VERSION 5.7 ;
  NOWIREEXTENSIONATPIN ON ;
  DIVIDERCHAR "/" ;
  BUSBITCHARS "[]" ;
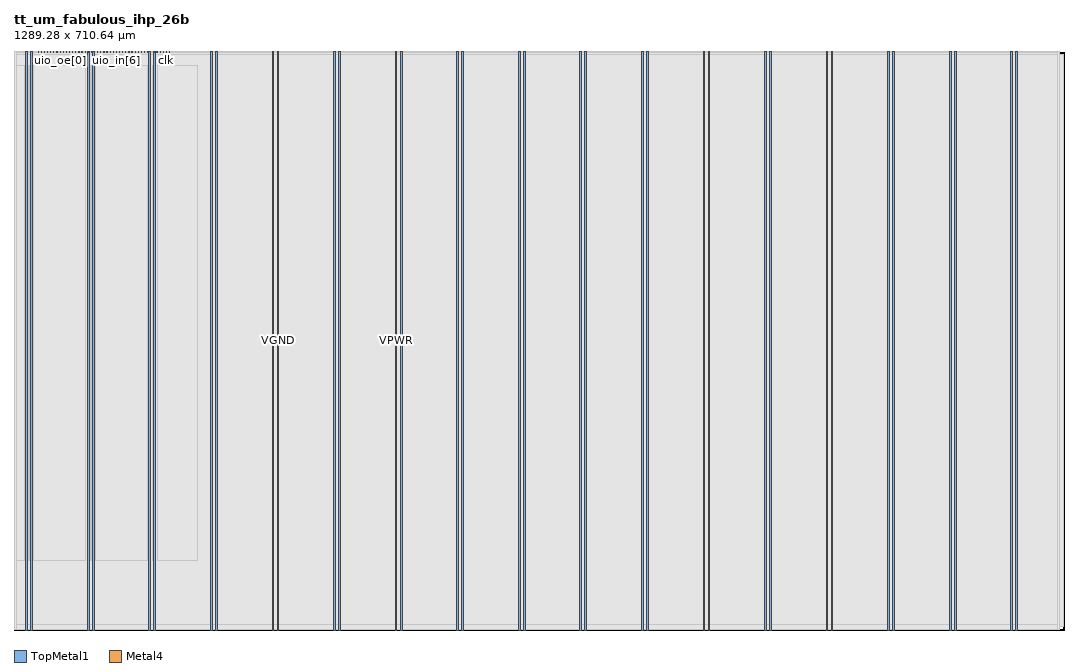
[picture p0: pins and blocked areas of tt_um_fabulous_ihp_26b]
MACRO tt_um_fabulous_ihp_26b
  CLASS BLOCK ;
  FOREIGN tt_um_fabulous_ihp_26b ;
  ORIGIN 0.000 0.000 ;
  SIZE 1289.280 BY 710.640 ;
  PIN VGND
    DIRECTION INOUT ;
    USE GROUND ;
    PORT
      LAYER TopMetal1 ;
        RECT 20.620 0.000 22.820 710.640 ;
    END
    PORT
      LAYER TopMetal1 ;
        RECT 96.220 0.000 98.420 710.640 ;
    END
    PORT
      LAYER TopMetal1 ;
        RECT 171.820 0.000 174.020 710.640 ;
    END
    PORT
      LAYER TopMetal1 ;
        RECT 247.420 0.000 249.620 710.640 ;
    END
    PORT
      LAYER TopMetal1 ;
        RECT 323.020 0.000 325.220 710.640 ;
    END
    PORT
      LAYER TopMetal1 ;
        RECT 398.620 0.000 400.820 710.640 ;
    END
    PORT
      LAYER TopMetal1 ;
        RECT 474.220 0.000 476.420 710.640 ;
    END
    PORT
      LAYER TopMetal1 ;
        RECT 549.820 0.000 552.020 710.640 ;
    END
    PORT
      LAYER TopMetal1 ;
        RECT 625.420 0.000 627.620 710.640 ;
    END
    PORT
      LAYER TopMetal1 ;
        RECT 701.020 0.000 703.220 710.640 ;
    END
    PORT
      LAYER TopMetal1 ;
        RECT 776.620 0.000 778.820 710.640 ;
    END
    PORT
      LAYER TopMetal1 ;
        RECT 852.220 0.000 854.420 710.640 ;
    END
    PORT
      LAYER TopMetal1 ;
        RECT 927.820 0.000 930.020 710.640 ;
    END
    PORT
      LAYER TopMetal1 ;
        RECT 1003.420 0.000 1005.620 710.640 ;
    END
    PORT
      LAYER TopMetal1 ;
        RECT 1079.020 0.000 1081.220 710.640 ;
    END
    PORT
      LAYER TopMetal1 ;
        RECT 1154.620 0.000 1156.820 710.640 ;
    END
    PORT
      LAYER TopMetal1 ;
        RECT 1230.220 0.000 1232.420 710.640 ;
    END
  END VGND
  PIN VPWR
    DIRECTION INOUT ;
    USE POWER ;
    PORT
      LAYER TopMetal1 ;
        RECT 14.420 0.000 16.620 710.640 ;
    END
    PORT
      LAYER TopMetal1 ;
        RECT 90.020 0.000 92.220 710.640 ;
    END
    PORT
      LAYER TopMetal1 ;
        RECT 165.620 0.000 167.820 710.640 ;
    END
    PORT
      LAYER TopMetal1 ;
        RECT 241.220 0.000 243.420 710.640 ;
    END
    PORT
      LAYER TopMetal1 ;
        RECT 316.820 0.000 319.020 710.640 ;
    END
    PORT
      LAYER TopMetal1 ;
        RECT 392.420 0.000 394.620 710.640 ;
    END
    PORT
      LAYER TopMetal1 ;
        RECT 468.020 0.000 470.220 710.640 ;
    END
    PORT
      LAYER TopMetal1 ;
        RECT 543.620 0.000 545.820 710.640 ;
    END
    PORT
      LAYER TopMetal1 ;
        RECT 619.220 0.000 621.420 710.640 ;
    END
    PORT
      LAYER TopMetal1 ;
        RECT 694.820 0.000 697.020 710.640 ;
    END
    PORT
      LAYER TopMetal1 ;
        RECT 770.420 0.000 772.620 710.640 ;
    END
    PORT
      LAYER TopMetal1 ;
        RECT 846.020 0.000 848.220 710.640 ;
    END
    PORT
      LAYER TopMetal1 ;
        RECT 921.620 0.000 923.820 710.640 ;
    END
    PORT
      LAYER TopMetal1 ;
        RECT 997.220 0.000 999.420 710.640 ;
    END
    PORT
      LAYER TopMetal1 ;
        RECT 1072.820 0.000 1075.020 710.640 ;
    END
    PORT
      LAYER TopMetal1 ;
        RECT 1148.420 0.000 1150.620 710.640 ;
    END
    PORT
      LAYER TopMetal1 ;
        RECT 1224.020 0.000 1226.220 710.640 ;
    END
  END VPWR
  PIN clk
    DIRECTION INPUT ;
    USE SIGNAL ;
    ANTENNAGATEAREA 2.901600 ;
    PORT
      LAYER Metal4 ;
        RECT 187.050 709.640 187.350 710.640 ;
    END
  END clk
  PIN ena
    DIRECTION INPUT ;
    USE SIGNAL ;
    PORT
      LAYER Metal4 ;
        RECT 190.890 709.640 191.190 710.640 ;
    END
  END ena
  PIN rst_n
    DIRECTION INPUT ;
    USE SIGNAL ;
    ANTENNAGATEAREA 0.180700 ;
    PORT
      LAYER Metal4 ;
        RECT 183.210 709.640 183.510 710.640 ;
    END
  END rst_n
  PIN ui_in[0]
    DIRECTION INPUT ;
    USE SIGNAL ;
    ANTENNAGATEAREA 0.180700 ;
    PORT
      LAYER Metal4 ;
        RECT 179.370 709.640 179.670 710.640 ;
    END
  END ui_in[0]
  PIN ui_in[1]
    DIRECTION INPUT ;
    USE SIGNAL ;
    ANTENNAGATEAREA 0.180700 ;
    PORT
      LAYER Metal4 ;
        RECT 175.530 709.640 175.830 710.640 ;
    END
  END ui_in[1]
  PIN ui_in[2]
    DIRECTION INPUT ;
    USE SIGNAL ;
    ANTENNAGATEAREA 0.335400 ;
    PORT
      LAYER Metal4 ;
        RECT 171.690 709.640 171.990 710.640 ;
    END
  END ui_in[2]
  PIN ui_in[3]
    DIRECTION INPUT ;
    USE SIGNAL ;
    ANTENNAGATEAREA 0.335400 ;
    PORT
      LAYER Metal4 ;
        RECT 167.850 709.640 168.150 710.640 ;
    END
  END ui_in[3]
  PIN ui_in[4]
    DIRECTION INPUT ;
    USE SIGNAL ;
    ANTENNAGATEAREA 0.335400 ;
    PORT
      LAYER Metal4 ;
        RECT 164.010 709.640 164.310 710.640 ;
    END
  END ui_in[4]
  PIN ui_in[5]
    DIRECTION INPUT ;
    USE SIGNAL ;
    ANTENNAGATEAREA 0.335400 ;
    PORT
      LAYER Metal4 ;
        RECT 160.170 709.640 160.470 710.640 ;
    END
  END ui_in[5]
  PIN ui_in[6]
    DIRECTION INPUT ;
    USE SIGNAL ;
    ANTENNAGATEAREA 0.335400 ;
    PORT
      LAYER Metal4 ;
        RECT 156.330 709.640 156.630 710.640 ;
    END
  END ui_in[6]
  PIN ui_in[7]
    DIRECTION INPUT ;
    USE SIGNAL ;
    ANTENNAGATEAREA 0.335400 ;
    ANTENNADIFFAREA 2.015400 ;
    PORT
      LAYER Metal4 ;
        RECT 152.490 709.640 152.790 710.640 ;
    END
  END ui_in[7]
  PIN uio_in[0]
    DIRECTION INPUT ;
    USE SIGNAL ;
    ANTENNAGATEAREA 0.335400 ;
    PORT
      LAYER Metal4 ;
        RECT 148.650 709.640 148.950 710.640 ;
    END
  END uio_in[0]
  PIN uio_in[1]
    DIRECTION INPUT ;
    USE SIGNAL ;
    ANTENNAGATEAREA 0.335400 ;
    PORT
      LAYER Metal4 ;
        RECT 144.810 709.640 145.110 710.640 ;
    END
  END uio_in[1]
  PIN uio_in[2]
    DIRECTION INPUT ;
    USE SIGNAL ;
    ANTENNAGATEAREA 0.289900 ;
    PORT
      LAYER Metal4 ;
        RECT 140.970 709.640 141.270 710.640 ;
    END
  END uio_in[2]
  PIN uio_in[3]
    DIRECTION INPUT ;
    USE SIGNAL ;
    ANTENNAGATEAREA 0.335400 ;
    PORT
      LAYER Metal4 ;
        RECT 137.130 709.640 137.430 710.640 ;
    END
  END uio_in[3]
  PIN uio_in[4]
    DIRECTION INPUT ;
    USE SIGNAL ;
    ANTENNAGATEAREA 0.335400 ;
    PORT
      LAYER Metal4 ;
        RECT 133.290 709.640 133.590 710.640 ;
    END
  END uio_in[4]
  PIN uio_in[5]
    DIRECTION INPUT ;
    USE SIGNAL ;
    ANTENNAGATEAREA 0.335400 ;
    ANTENNADIFFAREA 2.015400 ;
    PORT
      LAYER Metal4 ;
        RECT 129.450 709.640 129.750 710.640 ;
    END
  END uio_in[5]
  PIN uio_in[6]
    DIRECTION INPUT ;
    USE SIGNAL ;
    ANTENNAGATEAREA 0.289900 ;
    PORT
      LAYER Metal4 ;
        RECT 125.610 709.640 125.910 710.640 ;
    END
  END uio_in[6]
  PIN uio_in[7]
    DIRECTION INPUT ;
    USE SIGNAL ;
    ANTENNAGATEAREA 0.335400 ;
    ANTENNADIFFAREA 2.015400 ;
    PORT
      LAYER Metal4 ;
        RECT 121.770 709.640 122.070 710.640 ;
    END
  END uio_in[7]
  PIN uio_oe[0]
    DIRECTION OUTPUT ;
    USE SIGNAL ;
    ANTENNADIFFAREA 0.708600 ;
    PORT
      LAYER Metal4 ;
        RECT 56.490 709.640 56.790 710.640 ;
    END
  END uio_oe[0]
  PIN uio_oe[1]
    DIRECTION OUTPUT ;
    USE SIGNAL ;
    ANTENNADIFFAREA 0.708600 ;
    PORT
      LAYER Metal4 ;
        RECT 52.650 709.640 52.950 710.640 ;
    END
  END uio_oe[1]
  PIN uio_oe[2]
    DIRECTION OUTPUT ;
    USE SIGNAL ;
    ANTENNADIFFAREA 0.708600 ;
    PORT
      LAYER Metal4 ;
        RECT 48.810 709.640 49.110 710.640 ;
    END
  END uio_oe[2]
  PIN uio_oe[3]
    DIRECTION OUTPUT ;
    USE SIGNAL ;
    ANTENNADIFFAREA 0.708600 ;
    PORT
      LAYER Metal4 ;
        RECT 44.970 709.640 45.270 710.640 ;
    END
  END uio_oe[3]
  PIN uio_oe[4]
    DIRECTION OUTPUT ;
    USE SIGNAL ;
    ANTENNADIFFAREA 0.708600 ;
    PORT
      LAYER Metal4 ;
        RECT 41.130 709.640 41.430 710.640 ;
    END
  END uio_oe[4]
  PIN uio_oe[5]
    DIRECTION OUTPUT ;
    USE SIGNAL ;
    ANTENNADIFFAREA 0.708600 ;
    PORT
      LAYER Metal4 ;
        RECT 37.290 709.640 37.590 710.640 ;
    END
  END uio_oe[5]
  PIN uio_oe[6]
    DIRECTION OUTPUT ;
    USE SIGNAL ;
    ANTENNADIFFAREA 0.708600 ;
    PORT
      LAYER Metal4 ;
        RECT 33.450 709.640 33.750 710.640 ;
    END
  END uio_oe[6]
  PIN uio_oe[7]
    DIRECTION OUTPUT ;
    USE SIGNAL ;
    ANTENNADIFFAREA 0.708600 ;
    PORT
      LAYER Metal4 ;
        RECT 29.610 709.640 29.910 710.640 ;
    END
  END uio_oe[7]
  PIN uio_out[0]
    DIRECTION OUTPUT ;
    USE SIGNAL ;
    ANTENNADIFFAREA 0.708600 ;
    PORT
      LAYER Metal4 ;
        RECT 87.210 709.640 87.510 710.640 ;
    END
  END uio_out[0]
  PIN uio_out[1]
    DIRECTION OUTPUT ;
    USE SIGNAL ;
    ANTENNADIFFAREA 0.708600 ;
    PORT
      LAYER Metal4 ;
        RECT 83.370 709.640 83.670 710.640 ;
    END
  END uio_out[1]
  PIN uio_out[2]
    DIRECTION OUTPUT ;
    USE SIGNAL ;
    ANTENNADIFFAREA 0.708600 ;
    PORT
      LAYER Metal4 ;
        RECT 79.530 709.640 79.830 710.640 ;
    END
  END uio_out[2]
  PIN uio_out[3]
    DIRECTION OUTPUT ;
    USE SIGNAL ;
    ANTENNADIFFAREA 0.708600 ;
    PORT
      LAYER Metal4 ;
        RECT 75.690 709.640 75.990 710.640 ;
    END
  END uio_out[3]
  PIN uio_out[4]
    DIRECTION OUTPUT ;
    USE SIGNAL ;
    ANTENNADIFFAREA 0.708600 ;
    PORT
      LAYER Metal4 ;
        RECT 71.850 709.640 72.150 710.640 ;
    END
  END uio_out[4]
  PIN uio_out[5]
    DIRECTION OUTPUT ;
    USE SIGNAL ;
    ANTENNADIFFAREA 0.708600 ;
    PORT
      LAYER Metal4 ;
        RECT 68.010 709.640 68.310 710.640 ;
    END
  END uio_out[5]
  PIN uio_out[6]
    DIRECTION OUTPUT ;
    USE SIGNAL ;
    ANTENNADIFFAREA 0.708600 ;
    PORT
      LAYER Metal4 ;
        RECT 64.170 709.640 64.470 710.640 ;
    END
  END uio_out[6]
  PIN uio_out[7]
    DIRECTION OUTPUT ;
    USE SIGNAL ;
    ANTENNADIFFAREA 0.708600 ;
    PORT
      LAYER Metal4 ;
        RECT 60.330 709.640 60.630 710.640 ;
    END
  END uio_out[7]
  PIN uo_out[0]
    DIRECTION OUTPUT ;
    USE SIGNAL ;
    ANTENNADIFFAREA 0.708600 ;
    PORT
      LAYER Metal4 ;
        RECT 117.930 709.640 118.230 710.640 ;
    END
  END uo_out[0]
  PIN uo_out[1]
    DIRECTION OUTPUT ;
    USE SIGNAL ;
    ANTENNADIFFAREA 0.708600 ;
    PORT
      LAYER Metal4 ;
        RECT 114.090 709.640 114.390 710.640 ;
    END
  END uo_out[1]
  PIN uo_out[2]
    DIRECTION OUTPUT ;
    USE SIGNAL ;
    ANTENNADIFFAREA 0.708600 ;
    PORT
      LAYER Metal4 ;
        RECT 110.250 709.640 110.550 710.640 ;
    END
  END uo_out[2]
  PIN uo_out[3]
    DIRECTION OUTPUT ;
    USE SIGNAL ;
    ANTENNADIFFAREA 0.708600 ;
    PORT
      LAYER Metal4 ;
        RECT 106.410 709.640 106.710 710.640 ;
    END
  END uo_out[3]
  PIN uo_out[4]
    DIRECTION OUTPUT ;
    USE SIGNAL ;
    ANTENNADIFFAREA 0.708600 ;
    PORT
      LAYER Metal4 ;
        RECT 102.570 709.640 102.870 710.640 ;
    END
  END uo_out[4]
  PIN uo_out[5]
    DIRECTION OUTPUT ;
    USE SIGNAL ;
    ANTENNADIFFAREA 0.708600 ;
    PORT
      LAYER Metal4 ;
        RECT 98.730 709.640 99.030 710.640 ;
    END
  END uo_out[5]
  PIN uo_out[6]
    DIRECTION OUTPUT ;
    USE SIGNAL ;
    ANTENNADIFFAREA 0.708600 ;
    PORT
      LAYER Metal4 ;
        RECT 94.890 709.640 95.190 710.640 ;
    END
  END uo_out[6]
  PIN uo_out[7]
    DIRECTION OUTPUT ;
    USE SIGNAL ;
    ANTENNADIFFAREA 0.708600 ;
    PORT
      LAYER Metal4 ;
        RECT 91.050 709.640 91.350 710.640 ;
    END
  END uo_out[7]
  OBS
      LAYER GatPoly ;
        RECT 1.920 4.050 1288.800 707.010 ;
      LAYER Metal1 ;
        RECT 1.920 3.980 1288.800 707.080 ;
      LAYER Metal2 ;
        RECT 0.375 0.420 1284.105 710.365 ;
      LAYER Metal3 ;
        RECT 0.335 0.740 1284.145 710.325 ;
      LAYER Metal4 ;
        RECT 3.255 709.430 29.400 710.365 ;
        RECT 30.120 709.430 33.240 710.365 ;
        RECT 33.960 709.430 37.080 710.365 ;
        RECT 37.800 709.430 40.920 710.365 ;
        RECT 41.640 709.430 44.760 710.365 ;
        RECT 45.480 709.430 48.600 710.365 ;
        RECT 49.320 709.430 52.440 710.365 ;
        RECT 53.160 709.430 56.280 710.365 ;
        RECT 57.000 709.430 60.120 710.365 ;
        RECT 60.840 709.430 63.960 710.365 ;
        RECT 64.680 709.430 67.800 710.365 ;
        RECT 68.520 709.430 71.640 710.365 ;
        RECT 72.360 709.430 75.480 710.365 ;
        RECT 76.200 709.430 79.320 710.365 ;
        RECT 80.040 709.430 83.160 710.365 ;
        RECT 83.880 709.430 87.000 710.365 ;
        RECT 87.720 709.430 90.840 710.365 ;
        RECT 91.560 709.430 94.680 710.365 ;
        RECT 95.400 709.430 98.520 710.365 ;
        RECT 99.240 709.430 102.360 710.365 ;
        RECT 103.080 709.430 106.200 710.365 ;
        RECT 106.920 709.430 110.040 710.365 ;
        RECT 110.760 709.430 113.880 710.365 ;
        RECT 114.600 709.430 117.720 710.365 ;
        RECT 118.440 709.430 121.560 710.365 ;
        RECT 122.280 709.430 125.400 710.365 ;
        RECT 126.120 709.430 129.240 710.365 ;
        RECT 129.960 709.430 133.080 710.365 ;
        RECT 133.800 709.430 136.920 710.365 ;
        RECT 137.640 709.430 140.760 710.365 ;
        RECT 141.480 709.430 144.600 710.365 ;
        RECT 145.320 709.430 148.440 710.365 ;
        RECT 149.160 709.430 152.280 710.365 ;
        RECT 153.000 709.430 156.120 710.365 ;
        RECT 156.840 709.430 159.960 710.365 ;
        RECT 160.680 709.430 163.800 710.365 ;
        RECT 164.520 709.430 167.640 710.365 ;
        RECT 168.360 709.430 171.480 710.365 ;
        RECT 172.200 709.430 175.320 710.365 ;
        RECT 176.040 709.430 179.160 710.365 ;
        RECT 179.880 709.430 183.000 710.365 ;
        RECT 183.720 709.430 186.840 710.365 ;
        RECT 187.560 709.430 190.680 710.365 ;
        RECT 191.400 709.430 1281.225 710.365 ;
        RECT 3.255 0.420 1281.225 709.430 ;
      LAYER Metal5 ;
        RECT 3.215 7.250 1281.265 707.170 ;
      LAYER TopMetal1 ;
        RECT 3.100 85.280 12.780 692.980 ;
        RECT 18.260 85.280 18.980 692.980 ;
        RECT 24.460 85.280 88.380 692.980 ;
        RECT 93.860 85.280 94.580 692.980 ;
        RECT 100.060 85.280 163.980 692.980 ;
        RECT 169.460 85.280 170.180 692.980 ;
        RECT 175.660 85.280 225.900 692.980 ;
  END
END tt_um_fabulous_ihp_26b
END LIBRARY

